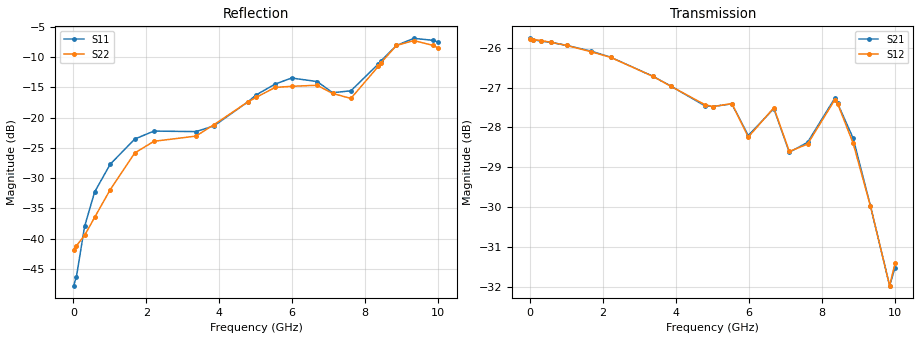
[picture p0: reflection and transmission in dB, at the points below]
! Device ID: PE43705
! Serial: 1
! Insertion: A
! Impedance: 50 ohm
! Temp: 25C
! VDD: 3.400V
! Attenuation Step: 24.75dB
#  Hz  S  RI  R  50
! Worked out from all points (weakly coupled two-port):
!   401 points, 10 MHz to 10.01 GHz, reference 50 ohm
!   highest |S21| = -25.76 dB at 10 MHz (marker M1); lowest = -32.0 dB at 9.86 GHz (marker M2)
!   lowest |S11| = -47.8 dB at 10 MHz (marker M3), VSWR 1.01, Z = 49.6 + j0.044 ohm
!   |S11| at or under -10 dB: start of sweep to 8.523 GHz
!   |S22| runs from -41.8 to -7.3 dB; largest |S21 - S12| = 0.00067
!   S11 on the Smith chart (normalised r, x): 10 MHz: 0.99, +0.00; 4.785 GHz: 0.79, +0.12; 8.435 GHz: 0.79, +0.50; 9.335 GHz: 0.51, +0.53; 10.01 GHz: 0.46, +0.31
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1e7  -0.00406 0.000444  0.0515 -0.000238  0.0514 -0.000175  0.0081 0.000276
8.5e7  -0.00381 0.00298  0.0513 -0.00123  0.0513 -0.00122  0.0084 0.00235
3.1e8  -0.00637 0.0109  0.0509 -0.0042  0.051 -0.0042  0.00592 0.00885
5.85e8  -0.0149 0.0192  0.0503 -0.00778  0.0503 -0.00781  -0.00161 0.0149
1.01e9  -0.035 0.0215  0.0487 -0.0132  0.0487 -0.0132  -0.0206 0.0147
1.685e9  -0.0659 0.0086  0.0451 -0.0207  0.045 -0.0207  -0.0509 0.00218
2.21e9  -0.0769 -0.00748  0.0412 -0.0261  0.0413 -0.0259  -0.0628 -0.0101
3.36e9  -0.0763 -0.0056  0.0308 -0.0344  0.0308 -0.0344  -0.0702 -0.0016
3.86e9  -0.0832 0.0189  0.0261 -0.0365  0.0262 -0.0364  -0.0857 0.0174
4.785e9  -0.1129 0.0736  0.0182 -0.0383  0.0183 -0.0384  -0.1195 0.0618
5.01e9  -0.1266 0.0867  0.0166 -0.0389  0.0168 -0.0388  -0.1281 0.0712
5.535e9  -0.1578 0.1042  0.0123 -0.0408  0.0121 -0.0409  -0.1501 0.0943
5.985e9  -0.1811 0.1099  0.00828 -0.038  0.00839 -0.0378  -0.1497 0.1017
6.685e9  -0.1732 0.0964  0.00449 -0.0418  0.00448 -0.0419  -0.1512 0.106
7.11e9  -0.1387 0.0804  -0.00191 -0.037  -0.00168 -0.0371  -0.1103 0.1131
7.61e9  -0.0957 0.1359  -0.00158 -0.0381  -0.00169 -0.0379  -0.0549 0.1329
8.36e9  -0.0328 0.2743  -0.0125 -0.0415  -0.0125 -0.0413  -0.0185 0.2633
8.435e9  -0.0352 0.2913  -0.0143 -0.0402  -0.0139 -0.0403  -0.0197 0.2826
8.86e9  -0.0868 0.3839  -0.0195 -0.0333  -0.0189 -0.033  -0.0675 0.3879
9.335e9  -0.1817 0.4122  -0.0183 -0.0259  -0.0183 -0.0259  -0.1549 0.4034
9.86e9  -0.2914 0.322  -0.0096 -0.0233  -0.00983 -0.0232  -0.2685 0.2884
1.001e10  -0.3156 0.2759  -0.00701 -0.0256  -0.00689 -0.026  -0.2962 0.2283
